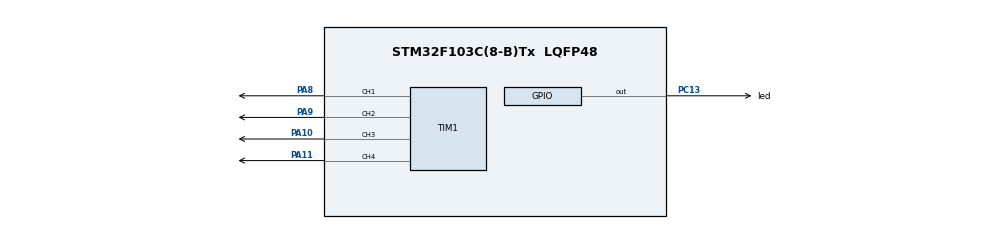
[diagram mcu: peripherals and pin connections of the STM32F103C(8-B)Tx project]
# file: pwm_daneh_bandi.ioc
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Mcu.Family=STM32F1
Mcu.Name=STM32F103C(8-B)Tx
Mcu.Package=LQFP48
NVIC.PriorityGroup=NVIC_PRIORITYGROUP_4
PA10.Signal=S_TIM1_CH3
PA11.Signal=S_TIM1_CH4
PA8.Signal=S_TIM1_CH1
PA9.Signal=S_TIM1_CH2
PC13-TAMPER-RTC.GPIO_Label=led
PC13-TAMPER-RTC.Signal=GPIO_Output
PD0-OSC_IN.Mode=HSE-External-Oscillator
PD0-OSC_IN.Signal=RCC_OSC_IN
PD1-OSC_OUT.Mode=HSE-External-Oscillator
PD1-OSC_OUT.Signal=RCC_OSC_OUT
ProjectManager.HeapSize=0x200
ProjectManager.StackSize=0x400
ProjectManager.TargetToolchain=MDK-ARM V5.32
RCC.AHBFreq_Value=16000000
RCC.APB1Freq_Value=16000000
RCC.APB1TimFreq_Value=16000000
RCC.APB2CLKDivider=RCC_HCLK_DIV16
RCC.APB2Freq_Value=1000000
RCC.APB2TimFreq_Value=2000000
RCC.EnbaleCSS=true
RCC.HCLKFreq_Value=16000000
RCC.PLLSourceVirtual=RCC_PLLSOURCE_HSE
RCC.SYSCLKFreq_VALUE=16000000
RCC.SYSCLKSource=RCC_SYSCLKSOURCE_PLLCLK
RCC.USBFreq_Value=16000000
SH.S_TIM1_CH1.0=TIM1_CH1,PWM Generation1 CH1
SH.S_TIM1_CH2.0=TIM1_CH2,PWM Generation2 CH2
SH.S_TIM1_CH3.0=TIM1_CH3,PWM Generation3 CH3
SH.S_TIM1_CH4.0=TIM1_CH4,PWM Generation4 CH4
TIM1.Channel-PWM\ Generation1\ CH1=TIM_CHANNEL_1
TIM1.Channel-PWM\ Generation2\ CH2=TIM_CHANNEL_2
TIM1.Channel-PWM\ Generation3\ CH3=TIM_CHANNEL_3
TIM1.Channel-PWM\ Generation4\ CH4=TIM_CHANNEL_4
VP_SYS_VS_ND.Mode=No_Debug
board=custom

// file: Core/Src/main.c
#include "main.h"

TIM_HandleTypeDef htim1;
void SystemClock_Config(void);
static void MX_GPIO_Init(void);
static void MX_TIM1_Init(void);

int period_value=30000;

int main(void)
{
  HAL_Init();
  SystemClock_Config();
  MX_GPIO_Init();
  MX_TIM1_Init();

/////////////////declare variables///////////////////

	int delay_value=1000/30;   // 1000/freq of pwm for led  PC13

///////////////configuration of TIM1/////////////////

	int cpmpare_value1=period_value*0.5; // defining the duty cycle of pwm //
	int cpmpare_value2=period_value*0.01; // defining the duty cycle of pwm //
	int cpmpare_value3=period_value*0.7; // defining the duty cycle of pwm //
	int cpmpare_value4=period_value*0.9; // defining the duty cycle of pwm //

	// setting the values //
	__HAL_TIM_SET_COMPARE(&htim1,TIM_CHANNEL_1,cpmpare_value1);
	__HAL_TIM_SET_COMPARE(&htim1,TIM_CHANNEL_2,cpmpare_value2);
	__HAL_TIM_SET_COMPARE(&htim1,TIM_CHANNEL_3,cpmpare_value3);
	__HAL_TIM_SET_COMPARE(&htim1,TIM_CHANNEL_4,cpmpare_value4);

	//starting timers//
	HAL_TIM_PWM_Start(&htim1,TIM_CHANNEL_1);
	HAL_TIM_PWM_Start(&htim1,TIM_CHANNEL_2);
	HAL_TIM_PWM_Start(&htim1,TIM_CHANNEL_3);
	HAL_TIM_PWM_Start(&htim1,TIM_CHANNEL_4);

  while (1)
  {
		HAL_GPIO_WritePin(led_GPIO_Port,led_Pin,1);
		HAL_Delay(delay_value/2);
		HAL_GPIO_WritePin(led_GPIO_Port,led_Pin,0);
		HAL_Delay(delay_value/2);

  }
}

void SystemClock_Config(void)
{
  RCC_OscInitTypeDef RCC_OscInitStruct = {0};
  RCC_ClkInitTypeDef RCC_ClkInitStruct = {0};

  /** Initializes the RCC Oscillators according to the specified parameters
  * in the RCC_OscInitTypeDef structure.
  */
  RCC_OscInitStruct.OscillatorType = RCC_OSCILLATORTYPE_HSE;
  RCC_OscInitStruct.HSEState = RCC_HSE_ON;
  RCC_OscInitStruct.HSEPredivValue = RCC_HSE_PREDIV_DIV1;
  RCC_OscInitStruct.HSIState = RCC_HSI_ON;
  RCC_OscInitStruct.PLL.PLLState = RCC_PLL_ON;
  RCC_OscInitStruct.PLL.PLLSource = RCC_PLLSOURCE_HSE;
  RCC_OscInitStruct.PLL.PLLMUL = RCC_PLL_MUL2;
  if (HAL_RCC_OscConfig(&RCC_OscInitStruct) != HAL_OK)
  {
    Error_Handler();
  }

  /** Initializes the CPU, AHB and APB buses clocks
  */
  RCC_ClkInitStruct.ClockType = RCC_CLOCKTYPE_HCLK|RCC_CLOCKTYPE_SYSCLK
                              |RCC_CLOCKTYPE_PCLK1|RCC_CLOCKTYPE_PCLK2;
  RCC_ClkInitStruct.SYSCLKSource = RCC_SYSCLKSOURCE_PLLCLK;
  RCC_ClkInitStruct.AHBCLKDivider = RCC_SYSCLK_DIV2;
  RCC_ClkInitStruct.APB1CLKDivider = RCC_HCLK_DIV1;
  RCC_ClkInitStruct.APB2CLKDivider = RCC_HCLK_DIV16;

  if (HAL_RCC_ClockConfig(&RCC_ClkInitStruct, FLASH_LATENCY_0) != HAL_OK)
  {
    Error_Handler();
  }

  /** Enables the Clock Security System
  */
  HAL_RCC_EnableCSS();
}

static void MX_TIM1_Init(void)
{

  TIM_MasterConfigTypeDef sMasterConfig = {0};
  TIM_OC_InitTypeDef sConfigOC = {0};
  TIM_BreakDeadTimeConfigTypeDef sBreakDeadTimeConfig = {0};

  htim1.Instance = TIM1;
  htim1.Init.Prescaler = 0;
  htim1.Init.CounterMode = TIM_COUNTERMODE_UP;
  htim1.Init.Period = period_value-1;
  htim1.Init.ClockDivision = TIM_CLOCKDIVISION_DIV1;
  htim1.Init.RepetitionCounter = 0;
  htim1.Init.AutoReloadPreload = TIM_AUTORELOAD_PRELOAD_DISABLE;
  if (HAL_TIM_PWM_Init(&htim1) != HAL_OK)
  {
    Error_Handler();
  }
  sMasterConfig.MasterOutputTrigger = TIM_TRGO_RESET;
  sMasterConfig.MasterSlaveMode = TIM_MASTERSLAVEMODE_DISABLE;
  if (HAL_TIMEx_MasterConfigSynchronization(&htim1, &sMasterConfig) != HAL_OK)
  {
    Error_Handler();
  }
  sConfigOC.OCMode = TIM_OCMODE_PWM1;
  sConfigOC.Pulse = 0;
  sConfigOC.OCPolarity = TIM_OCPOLARITY_HIGH;
  sConfigOC.OCNPolarity = TIM_OCNPOLARITY_HIGH;
  sConfigOC.OCFastMode = TIM_OCFAST_DISABLE;
  sConfigOC.OCIdleState = TIM_OCIDLESTATE_RESET;
  sConfigOC.OCNIdleState = TIM_OCNIDLESTATE_RESET;
  if (HAL_TIM_PWM_ConfigChannel(&htim1, &sConfigOC, TIM_CHANNEL_1) != HAL_OK)
  {
    Error_Handler();
  }
  if (HAL_TIM_PWM_ConfigChannel(&htim1, &sConfigOC, TIM_CHANNEL_2) != HAL_OK)
  {
    Error_Handler();
  }
  if (HAL_TIM_PWM_ConfigChannel(&htim1, &sConfigOC, TIM_CHANNEL_3) != HAL_OK)
  {
    Error_Handler();
  }
  if (HAL_TIM_PWM_ConfigChannel(&htim1, &sConfigOC, TIM_CHANNEL_4) != HAL_OK)
  {
    Error_Handler();
  }
  sBreakDeadTimeConfig.OffStateRunMode = TIM_OSSR_DISABLE;
  sBreakDeadTimeConfig.OffStateIDLEMode = TIM_OSSI_DISABLE;
  sBreakDeadTimeConfig.LockLevel = TIM_LOCKLEVEL_OFF;
  sBreakDeadTimeConfig.DeadTime = 0;
  sBreakDeadTimeConfig.BreakState = TIM_BREAK_DISABLE;
  sBreakDeadTimeConfig.BreakPolarity = TIM_BREAKPOLARITY_HIGH;
  sBreakDeadTimeConfig.AutomaticOutput = TIM_AUTOMATICOUTPUT_DISABLE;
  if (HAL_TIMEx_ConfigBreakDeadTime(&htim1, &sBreakDeadTimeConfig) != HAL_OK)
  {
    Error_Handler();
  }
  HAL_TIM_MspPostInit(&htim1);

}

static void MX_GPIO_Init(void)
{
  GPIO_InitTypeDef GPIO_InitStruct = {0};

  /* GPIO Ports Clock Enable */
  __HAL_RCC_GPIOC_CLK_ENABLE();
  __HAL_RCC_GPIOD_CLK_ENABLE();
  __HAL_RCC_GPIOA_CLK_ENABLE();

  /*Configure GPIO pin Output Level */
  HAL_GPIO_WritePin(led_GPIO_Port, led_Pin, GPIO_PIN_RESET);

  /*Configure GPIO pin : led_Pin */
  GPIO_InitStruct.Pin = led_Pin;
  GPIO_InitStruct.Mode = GPIO_MODE_OUTPUT_PP;
  GPIO_InitStruct.Pull = GPIO_NOPULL;
  GPIO_InitStruct.Speed = GPIO_SPEED_FREQ_LOW;
  HAL_GPIO_Init(led_GPIO_Port, &GPIO_InitStruct);

}

void Error_Handler(void)
{
  __disable_irq();
  while (1)
  {
  }
}
